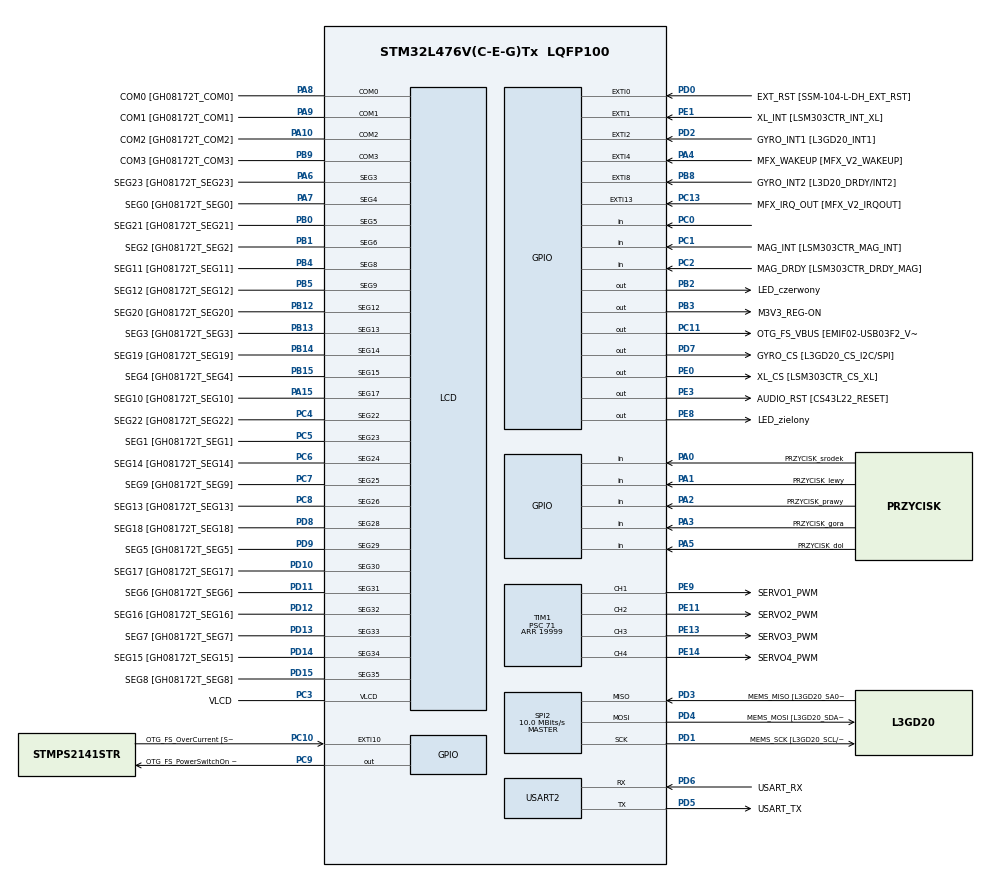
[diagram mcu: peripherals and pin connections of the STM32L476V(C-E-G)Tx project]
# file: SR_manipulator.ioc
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<<<<<<<< HEAD:manipulator/manipulator/manipulator.ioc
========
>>>>>>>> bceb7f419866e076b447dddfbb9c82c1b5c03c72:SR_manipulator/SR_manipulator.ioc
Mcu.Family=STM32L4
Mcu.Name=STM32L476V(C-E-G)Tx
Mcu.Package=LQFP100
<<<<<<<< HEAD:manipulator/manipulator/manipulator.ioc
NVIC.PriorityGroup=NVIC_PRIORITYGROUP_4
PA0.GPIO_Label=JOY_CENTER [MT-008A_CENTER]
========
NVIC.PriorityGroup=NVIC_PRIORITYGROUP_4
PA0.GPIO_Label=PRZYCISK_srodek
>>>>>>>> bceb7f419866e076b447dddfbb9c82c1b5c03c72:SR_manipulator/SR_manipulator.ioc
PA0.GPIO_Mode=GPIO_MODE_INPUT
PA0.GPIO_PuPd=GPIO_PULLDOWN
PA0.Signal=GPIO_Input
<<<<<<<< HEAD:manipulator/manipulator/manipulator.ioc
PA1.GPIO_Label=JOY_LEFT [MT-008A_LEFT]
========
PA1.GPIO_Label=PRZYCISK_lewy
>>>>>>>> bceb7f419866e076b447dddfbb9c82c1b5c03c72:SR_manipulator/SR_manipulator.ioc
PA1.GPIO_Mode=GPIO_MODE_INPUT
PA1.GPIO_PuPd=GPIO_PULLDOWN
PA1.Signal=GPIO_Input
PA10.GPIO_Label=COM2 [GH08172T_COM2]
PA10.GPIO_Mode=GPIO_MODE_AF_PP
PA10.GPIO_PuPd=GPIO_NOPULL
PA10.GPIO_Speed=GPIO_SPEED_FREQ_LOW
PA10.Mode=1/4 Duty Cycle
PA10.Signal=LCD_COM2
PA13\ (JTMS-SWDIO).GPIO_Label=SWDIO
PA13\ (JTMS-SWDIO).Mode=Serial_Wire
PA13\ (JTMS-SWDIO).Signal=SYS_JTMS-SWDIO
PA14\ (JTCK-SWCLK).GPIO_Label=SWCLK
PA14\ (JTCK-SWCLK).Mode=Serial_Wire
PA14\ (JTCK-SWCLK).Signal=SYS_JTCK-SWCLK
PA15\ (JTDI).GPIO_Label=SEG10 [GH08172T_SEG10]
PA15\ (JTDI).GPIO_Mode=GPIO_MODE_AF_PP
PA15\ (JTDI).GPIO_PuPd=GPIO_NOPULL
PA15\ (JTDI).GPIO_Speed=GPIO_SPEED_FREQ_LOW
PA15\ (JTDI).Mode=SEG17
PA15\ (JTDI).Signal=LCD_SEG17
<<<<<<<< HEAD:manipulator/manipulator/manipulator.ioc
PA2.GPIO_Label=JOY_RIGHT [MT-008A_RIGHT]
========
PA2.GPIO_Label=PRZYCISK_prawy
>>>>>>>> bceb7f419866e076b447dddfbb9c82c1b5c03c72:SR_manipulator/SR_manipulator.ioc
PA2.GPIO_Mode=GPIO_MODE_INPUT
PA2.GPIO_PuPd=GPIO_PULLDOWN
PA2.Signal=GPIO_Input
<<<<<<<< HEAD:manipulator/manipulator/manipulator.ioc
PA3.GPIO_Label=JOY_UP [MT-008A_UP]
========
PA3.GPIO_Label=PRZYCISK_gora
>>>>>>>> bceb7f419866e076b447dddfbb9c82c1b5c03c72:SR_manipulator/SR_manipulator.ioc
PA3.GPIO_Mode=GPIO_MODE_INPUT
PA3.GPIO_PuPd=GPIO_PULLDOWN
PA3.Signal=GPIO_Input
PA4.GPIO_Label=MFX_WAKEUP [MFX_V2_WAKEUP]
PA4.GPIO_ModeDefaultEXTI=GPIO_MODE_EVT_RISING
PA4.GPIO_PuPd=GPIO_NOPULL
PA4.Signal=GPXTI4
<<<<<<<< HEAD:manipulator/manipulator/manipulator.ioc
PA5.GPIO_Label=JOY_DOWN [MT-008A_DOWN]
========
PA5.GPIO_Label=PRZYCISK_dol
>>>>>>>> bceb7f419866e076b447dddfbb9c82c1b5c03c72:SR_manipulator/SR_manipulator.ioc
PA5.GPIO_Mode=GPIO_MODE_INPUT
PA5.GPIO_PuPd=GPIO_PULLDOWN
PA5.Signal=GPIO_Input
PA6.GPIO_Label=SEG23 [GH08172T_SEG23]
PA6.GPIO_Mode=GPIO_MODE_AF_PP
PA6.GPIO_PuPd=GPIO_NOPULL
PA6.GPIO_Speed=GPIO_SPEED_FREQ_LOW
PA6.Mode=SEG3
PA6.Signal=LCD_SEG3
PA7.GPIO_Label=SEG0 [GH08172T_SEG0]
PA7.GPIO_Mode=GPIO_MODE_AF_PP
PA7.GPIO_PuPd=GPIO_NOPULL
PA7.GPIO_Speed=GPIO_SPEED_FREQ_LOW
PA7.Mode=SEG4
PA7.Signal=LCD_SEG4
PA8.GPIO_Label=COM0 [GH08172T_COM0]
PA8.GPIO_Mode=GPIO_MODE_AF_PP
PA8.GPIO_PuPd=GPIO_NOPULL
PA8.GPIO_Speed=GPIO_SPEED_FREQ_LOW
PA8.Mode=1/4 Duty Cycle
PA8.Signal=LCD_COM0
PA9.GPIO_Label=COM1 [GH08172T_COM1]
PA9.GPIO_Mode=GPIO_MODE_AF_PP
PA9.GPIO_PuPd=GPIO_NOPULL
PA9.GPIO_Speed=GPIO_SPEED_FREQ_LOW
PA9.Mode=1/4 Duty Cycle
PA9.Signal=LCD_COM1
PB0.GPIO_Label=SEG21 [GH08172T_SEG21]
PB0.GPIO_Mode=GPIO_MODE_AF_PP
PB0.GPIO_PuPd=GPIO_NOPULL
PB0.GPIO_Speed=GPIO_SPEED_FREQ_LOW
PB0.Mode=SEG5
PB0.Signal=LCD_SEG5
PB1.GPIO_Label=SEG2 [GH08172T_SEG2]
PB1.GPIO_Mode=GPIO_MODE_AF_PP
PB1.GPIO_PuPd=GPIO_NOPULL
PB1.GPIO_Speed=GPIO_SPEED_FREQ_LOW
PB1.Mode=SEG6
PB1.Signal=LCD_SEG6
PB12.GPIO_Label=SEG20 [GH08172T_SEG20]
PB12.GPIO_Mode=GPIO_MODE_AF_PP
PB12.GPIO_PuPd=GPIO_NOPULL
PB12.GPIO_Speed=GPIO_SPEED_FREQ_LOW
PB12.Mode=SEG12
PB12.Signal=LCD_SEG12
PB13.GPIO_Label=SEG3 [GH08172T_SEG3]
PB13.GPIO_Mode=GPIO_MODE_AF_PP
PB13.GPIO_PuPd=GPIO_NOPULL
PB13.GPIO_Speed=GPIO_SPEED_FREQ_LOW
PB13.Mode=SEG13
PB13.Signal=LCD_SEG13
PB14.GPIO_Label=SEG19 [GH08172T_SEG19]
PB14.GPIO_Mode=GPIO_MODE_AF_PP
PB14.GPIO_PuPd=GPIO_NOPULL
PB14.GPIO_Speed=GPIO_SPEED_FREQ_LOW
PB14.Mode=SEG14
PB14.Signal=LCD_SEG14
PB15.GPIO_Label=SEG4 [GH08172T_SEG4]
PB15.GPIO_Mode=GPIO_MODE_AF_PP
PB15.GPIO_PuPd=GPIO_NOPULL
PB15.GPIO_Speed=GPIO_SPEED_FREQ_LOW
PB15.Mode=SEG15
PB15.Signal=LCD_SEG15
<<<<<<<< HEAD:manipulator/manipulator/manipulator.ioc
PB2.GPIO_Label=LD_R [LED red]
========
PB2.GPIO_Label=LED_czerwony
>>>>>>>> bceb7f419866e076b447dddfbb9c82c1b5c03c72:SR_manipulator/SR_manipulator.ioc
PB2.GPIO_ModeDefaultOutputPP=GPIO_MODE_OUTPUT_PP
PB2.GPIO_PuPd=GPIO_PULLUP
PB2.GPIO_Speed=GPIO_SPEED_FREQ_VERY_HIGH
PB2.Signal=GPIO_Output
PB3\ (JTDO-TRACESWO).GPIO_Label=M3V3_REG-ON
PB3\ (JTDO-TRACESWO).GPIO_ModeDefaultOutputPP=GPIO_MODE_OUTPUT_PP
PB3\ (JTDO-TRACESWO).GPIO_PuPd=GPIO_NOPULL
PB3\ (JTDO-TRACESWO).GPIO_Speed=GPIO_SPEED_FREQ_LOW
PB3\ (JTDO-TRACESWO).Signal=GPIO_Output
PB4\ (NJTRST).GPIO_Label=SEG11 [GH08172T_SEG11]
PB4\ (NJTRST).GPIO_Mode=GPIO_MODE_AF_PP
PB4\ (NJTRST).GPIO_PuPd=GPIO_NOPULL
PB4\ (NJTRST).GPIO_Speed=GPIO_SPEED_FREQ_LOW
PB4\ (NJTRST).Mode=SEG8
PB4\ (NJTRST).Signal=LCD_SEG8
PB5.GPIO_Label=SEG12 [GH08172T_SEG12]
PB5.GPIO_Mode=GPIO_MODE_AF_PP
PB5.GPIO_PuPd=GPIO_NOPULL
PB5.GPIO_Speed=GPIO_SPEED_FREQ_LOW
PB5.Mode=SEG9
PB5.Signal=LCD_SEG9
PB8.GPIO_Label=GYRO_INT2 [L3D20_DRDY/INT2]
PB8.GPIO_ModeDefaultEXTI=GPIO_MODE_EVT_RISING
PB8.GPIO_PuPd=GPIO_NOPULL
PB8.Signal=GPXTI8
PB9.GPIO_FM9=__NULL
PB9.GPIO_Label=COM3 [GH08172T_COM3]
PB9.GPIO_Mode=GPIO_MODE_AF_PP
PB9.GPIO_PuPd=GPIO_NOPULL
PB9.GPIO_Speed=GPIO_SPEED_FREQ_LOW
PB9.Mode=1/4 Duty Cycle
PB9.Signal=LCD_COM3
PC0.Signal=GPIO_Input
PC1.GPIO_Label=MAG_INT [LSM303CTR_MAG_INT]
PC1.GPIO_Mode=GPIO_MODE_INPUT
PC1.GPIO_PuPd=GPIO_NOPULL
PC1.Signal=GPIO_Input
PC10.GPIO_Label=OTG_FS_OverCurrent [STMPS2141STR_FAULT]
PC10.GPIO_ModeDefaultEXTI=GPIO_MODE_EVT_RISING
PC10.GPIO_PuPd=GPIO_NOPULL
PC10.Signal=GPXTI10
PC11.GPIO_Label=OTG_FS_VBUS [EMIF02-USB03F2_Vbus]
PC11.GPIO_ModeDefaultOutputPP=GPIO_MODE_OUTPUT_PP
PC11.GPIO_PuPd=GPIO_NOPULL
PC11.GPIO_Speed=GPIO_SPEED_FREQ_LOW
PC11.Signal=GPIO_Output
<<<<<<<< HEAD:manipulator/manipulator/manipulator.ioc
PC13.GPIO_Label=MFX_IRQ_OUT [MFX_V2_IRQOUT]
PC13.GPIO_ModeDefaultEXTI=GPIO_MODE_EVT_RISING
PC13.GPIO_PuPd=GPIO_NOPULL
PC13.Signal=GPXTI13
PC14-OSC32_IN\ (PC14).Mode=LSE-External-Oscillator
PC14-OSC32_IN\ (PC14).Signal=RCC_OSC32_IN
PC15-OSC32_OUT\ (PC15).Mode=LSE-External-Oscillator
PC15-OSC32_OUT\ (PC15).Signal=RCC_OSC32_OUT
========
>>>>>>>> bceb7f419866e076b447dddfbb9c82c1b5c03c72:SR_manipulator/SR_manipulator.ioc
PC2.GPIO_Label=MAG_DRDY [LSM303CTR_DRDY_MAG]
PC2.GPIO_Mode=GPIO_MODE_INPUT
PC2.GPIO_PuPd=GPIO_NOPULL
PC2.Signal=GPIO_Input
PC3.GPIO_Label=VLCD
PC3.GPIO_Mode=GPIO_MODE_AF_PP
PC3.GPIO_PuPd=GPIO_NOPULL
PC3.GPIO_Speed=GPIO_SPEED_FREQ_LOW
PC3.Mode=1/4 Duty Cycle
PC3.Signal=LCD_VLCD
PC4.GPIO_Label=SEG22 [GH08172T_SEG22]
PC4.GPIO_Mode=GPIO_MODE_AF_PP
PC4.GPIO_PuPd=GPIO_NOPULL
PC4.GPIO_Speed=GPIO_SPEED_FREQ_LOW
PC4.Mode=SEG22
PC4.Signal=LCD_SEG22
PC5.GPIO_Label=SEG1 [GH08172T_SEG1]
PC5.GPIO_Mode=GPIO_MODE_AF_PP
PC5.GPIO_PuPd=GPIO_NOPULL
PC5.GPIO_Speed=GPIO_SPEED_FREQ_LOW
PC5.Mode=SEG23
PC5.Signal=LCD_SEG23
PC6.GPIO_Label=SEG14 [GH08172T_SEG14]
PC6.GPIO_Mode=GPIO_MODE_AF_PP
PC6.GPIO_PuPd=GPIO_NOPULL
PC6.GPIO_Speed=GPIO_SPEED_FREQ_LOW
PC6.Mode=SEG24
PC6.Signal=LCD_SEG24
PC7.GPIO_Label=SEG9 [GH08172T_SEG9]
PC7.GPIO_Mode=GPIO_MODE_AF_PP
PC7.GPIO_PuPd=GPIO_NOPULL
PC7.GPIO_Speed=GPIO_SPEED_FREQ_LOW
PC7.Mode=SEG25
PC7.Signal=LCD_SEG25
PC8.GPIO_Label=SEG13 [GH08172T_SEG13]
PC8.GPIO_Mode=GPIO_MODE_AF_PP
PC8.GPIO_PuPd=GPIO_NOPULL
PC8.GPIO_Speed=GPIO_SPEED_FREQ_LOW
PC8.Mode=SEG26
PC8.Signal=LCD_SEG26
PC9.GPIO_Label=OTG_FS_PowerSwitchOn [STMPS2141STR_EN]
PC9.GPIO_ModeDefaultOutputPP=GPIO_MODE_OUTPUT_PP
PC9.GPIO_PuPd=GPIO_NOPULL
PC9.GPIO_Speed=GPIO_SPEED_FREQ_LOW
PC9.PinState=GPIO_PIN_SET
PC9.Signal=GPIO_Output
PD0.GPIO_Label=EXT_RST [SSM-104-L-DH_EXT_RST]
PD0.GPIO_ModeDefaultEXTI=GPIO_MODE_EVT_RISING
PD0.GPIO_PuPd=GPIO_NOPULL
PD0.Signal=GPXTI0
PD1.GPIO_Label=MEMS_SCK [L3GD20_SCL/SPC]
PD1.GPIO_Mode=GPIO_MODE_AF_PP
PD1.GPIO_PuPd=GPIO_NOPULL
PD1.GPIO_Speed=GPIO_SPEED_FREQ_VERY_HIGH
PD1.Mode=Full_Duplex_Master
PD1.Signal=SPI2_SCK
PD10.GPIO_Label=SEG17 [GH08172T_SEG17]
PD10.GPIO_Mode=GPIO_MODE_AF_PP
PD10.GPIO_PuPd=GPIO_NOPULL
PD10.GPIO_Speed=GPIO_SPEED_FREQ_LOW
PD10.Mode=SEG30
PD10.Signal=LCD_SEG30
PD11.GPIO_Label=SEG6 [GH08172T_SEG6]
PD11.GPIO_Mode=GPIO_MODE_AF_PP
PD11.GPIO_PuPd=GPIO_NOPULL
PD11.GPIO_Speed=GPIO_SPEED_FREQ_LOW
PD11.Mode=SEG31
PD11.Signal=LCD_SEG31
PD12.GPIO_Label=SEG16 [GH08172T_SEG16]
PD12.GPIO_Mode=GPIO_MODE_AF_PP
PD12.GPIO_PuPd=GPIO_NOPULL
PD12.GPIO_Speed=GPIO_SPEED_FREQ_LOW
PD12.Mode=SEG32
PD12.Signal=LCD_SEG32
PD13.GPIO_Label=SEG7 [GH08172T_SEG7]
PD13.GPIO_Mode=GPIO_MODE_AF_PP
PD13.GPIO_PuPd=GPIO_NOPULL
PD13.GPIO_Speed=GPIO_SPEED_FREQ_LOW
PD13.Mode=SEG33
PD13.Signal=LCD_SEG33
PD14.GPIO_Label=SEG15 [GH08172T_SEG15]
PD14.GPIO_Mode=GPIO_MODE_AF_PP
PD14.GPIO_PuPd=GPIO_NOPULL
PD14.GPIO_Speed=GPIO_SPEED_FREQ_LOW
PD14.Mode=SEG34
PD14.Signal=LCD_SEG34
PD15.GPIO_Label=SEG8 [GH08172T_SEG8]
PD15.GPIO_Mode=GPIO_MODE_AF_PP
PD15.GPIO_PuPd=GPIO_NOPULL
PD15.GPIO_Speed=GPIO_SPEED_FREQ_LOW
PD15.Mode=SEG35
PD15.Signal=LCD_SEG35
PD2.GPIO_Label=GYRO_INT1 [L3GD20_INT1]
PD2.GPIO_ModeDefaultEXTI=GPIO_MODE_EVT_RISING
PD2.GPIO_PuPd=GPIO_NOPULL
PD2.Signal=GPXTI2
PD3.GPIO_Label=MEMS_MISO [L3GD20_SA0/SDO]
PD3.GPIO_Mode=GPIO_MODE_AF_PP
PD3.GPIO_PuPd=GPIO_NOPULL
PD3.GPIO_Speed=GPIO_SPEED_FREQ_VERY_HIGH
PD3.Mode=Full_Duplex_Master
PD3.Signal=SPI2_MISO
PD4.GPIO_Label=MEMS_MOSI [L3GD20_SDA/SDI/SDO]
PD4.GPIO_Mode=GPIO_MODE_AF_PP
PD4.GPIO_PuPd=GPIO_NOPULL
PD4.GPIO_Speed=GPIO_SPEED_FREQ_VERY_HIGH
PD4.Mode=Full_Duplex_Master
PD4.Signal=SPI2_MOSI
PD5.GPIO_Label=USART_TX
PD5.GPIO_Mode=GPIO_MODE_AF_PP
PD5.GPIO_PuPd=GPIO_PULLUP
PD5.GPIO_Speed=GPIO_SPEED_FREQ_VERY_HIGH
PD5.Mode=Asynchronous
PD5.Signal=USART2_TX
PD6.GPIO_Label=USART_RX
PD6.GPIO_Mode=GPIO_MODE_AF_PP
PD6.GPIO_PuPd=GPIO_PULLUP
PD6.GPIO_Speed=GPIO_SPEED_FREQ_VERY_HIGH
PD6.Mode=Asynchronous
PD6.Signal=USART2_RX
PD7.GPIO_Label=GYRO_CS [L3GD20_CS_I2C/SPI]
PD7.GPIO_ModeDefaultOutputPP=GPIO_MODE_OUTPUT_PP
PD7.GPIO_PuPd=GPIO_NOPULL
PD7.GPIO_Speed=GPIO_SPEED_FREQ_VERY_HIGH
PD7.Signal=GPIO_Output
PD8.GPIO_Label=SEG18 [GH08172T_SEG18]
PD8.GPIO_Mode=GPIO_MODE_AF_PP
PD8.GPIO_PuPd=GPIO_NOPULL
PD8.GPIO_Speed=GPIO_SPEED_FREQ_LOW
PD8.Mode=SEG28
PD8.Signal=LCD_SEG28
PD9.GPIO_Label=SEG5 [GH08172T_SEG5]
PD9.GPIO_Mode=GPIO_MODE_AF_PP
PD9.GPIO_PuPd=GPIO_NOPULL
PD9.GPIO_Speed=GPIO_SPEED_FREQ_LOW
PD9.Mode=SEG29
PD9.Signal=LCD_SEG29
PE0.GPIO_Label=XL_CS [LSM303CTR_CS_XL]
PE0.GPIO_ModeDefaultOutputPP=GPIO_MODE_OUTPUT_PP
PE0.GPIO_PuPd=GPIO_NOPULL
PE0.GPIO_Speed=GPIO_SPEED_FREQ_LOW
PE0.Signal=GPIO_Output
PE1.GPIO_Label=XL_INT [LSM303CTR_INT_XL]
PE1.GPIO_ModeDefaultEXTI=GPIO_MODE_EVT_RISING
PE1.GPIO_PuPd=GPIO_NOPULL
PE1.Signal=GPXTI1
<<<<<<<< HEAD:manipulator/manipulator/manipulator.ioc
PE11.Signal=S_TIM1_CH2
PE13.Signal=S_TIM1_CH3
========
PE11.GPIO_Label=SERVO2_PWM
PE11.Signal=S_TIM1_CH2
PE13.GPIO_Label=SERVO3_PWM
PE13.Signal=S_TIM1_CH3
PE14.GPIO_Label=SERVO4_PWM
>>>>>>>> bceb7f419866e076b447dddfbb9c82c1b5c03c72:SR_manipulator/SR_manipulator.ioc
PE14.Signal=S_TIM1_CH4
PE3.GPIO_Label=AUDIO_RST [CS43L22_RESET]
PE3.GPIO_ModeDefaultOutputPP=GPIO_MODE_OUTPUT_PP
PE3.GPIO_PuPd=GPIO_NOPULL
PE3.GPIO_Speed=GPIO_SPEED_FREQ_HIGH
PE3.Signal=GPIO_Output
<<<<<<<< HEAD:manipulator/manipulator/manipulator.ioc
PE8.GPIO_Label=LD_G [LED_Green]
========
PE8.GPIO_Label=LED_zielony
>>>>>>>> bceb7f419866e076b447dddfbb9c82c1b5c03c72:SR_manipulator/SR_manipulator.ioc
PE8.GPIO_ModeDefaultOutputPP=GPIO_MODE_OUTPUT_PP
PE8.GPIO_PuPd=GPIO_PULLUP
PE8.GPIO_Speed=GPIO_SPEED_FREQ_VERY_HIGH
PE8.Signal=GPIO_Output
<<<<<<<< HEAD:manipulator/manipulator/manipulator.ioc
PE9.Signal=S_TIM1_CH1
PH0-OSC_IN\ (PH0).Mode=HSE-External-Oscillator
PH0-OSC_IN\ (PH0).Signal=RCC_OSC_IN
PH1-OSC_OUT\ (PH1).Mode=HSE-External-Oscillator
PH1-OSC_OUT\ (PH1).Signal=RCC_OSC_OUT
========
PE9.GPIO_Label=SERVO1_PWM
PE9.Signal=S_TIM1_CH1
>>>>>>>> bceb7f419866e076b447dddfbb9c82c1b5c03c72:SR_manipulator/SR_manipulator.ioc
<<<<<<<< HEAD:manipulator/manipulator/manipulator.ioc
========
>>>>>>>> bceb7f419866e076b447dddfbb9c82c1b5c03c72:SR_manipulator/SR_manipulator.ioc
ProjectManager.HeapSize=0x200
<<<<<<<< HEAD:manipulator/manipulator/manipulator.ioc
========
>>>>>>>> bceb7f419866e076b447dddfbb9c82c1b5c03c72:SR_manipulator/SR_manipulator.ioc
ProjectManager.StackSize=0x400
ProjectManager.TargetToolchain=STM32CubeIDE
<<<<<<<< HEAD:manipulator/manipulator/manipulator.ioc
RCC.ADCFreq_Value=48000000
RCC.AHBFreq_Value=72000000
RCC.APB1Freq_Value=72000000
RCC.APB1TimFreq_Value=72000000
RCC.APB2Freq_Value=72000000
RCC.APB2TimFreq_Value=72000000
RCC.CortexFreq_Value=72000000
RCC.HCLKFreq_Value=72000000
RCC.HSE_VALUE=8000000
RCC.HSI_VALUE=16000000
RCC.MSI_VALUE=4000000
RCC.PLLN=36
========
RCC.ADCFreq_Value=48000000
RCC.AHBCLKDivider=RCC_SYSCLK_DIV2
RCC.AHBFreq_Value=20000000
RCC.APB1Freq_Value=20000000
RCC.APB1TimFreq_Value=20000000
RCC.APB2Freq_Value=20000000
RCC.APB2TimFreq_Value=20000000
RCC.CortexFreq_Value=20000000
RCC.HCLKFreq_Value=20000000
RCC.HSE_VALUE=8000000
RCC.HSI_VALUE=16000000
RCC.LSE_VALUE=32768
RCC.MSI_VALUE=4000000
RCC.PLLN=20
>>>>>>>> bceb7f419866e076b447dddfbb9c82c1b5c03c72:SR_manipulator/SR_manipulator.ioc
RCC.PLLSAI1N=24
RCC.PREFETCH_ENABLE=1
<<<<<<<< HEAD:manipulator/manipulator/manipulator.ioc
========
>>>>>>>> bceb7f419866e076b447dddfbb9c82c1b5c03c72:SR_manipulator/SR_manipulator.ioc
<<<<<<<< HEAD:manipulator/manipulator/manipulator.ioc
RCC.SYSCLKFreq_VALUE=72000000
RCC.SYSCLKSource=RCC_SYSCLKSOURCE_PLLCLK
RCC.USBFreq_Value=48000000
RCC.VCOOutputFreq_Value=144000000
========
RCC.SYSCLKFreq_VALUE=40000000
RCC.SYSCLKSource=RCC_SYSCLKSOURCE_PLLCLK
RCC.USBFreq_Value=48000000
RCC.VCOOutputFreq_Value=80000000
>>>>>>>> bceb7f419866e076b447dddfbb9c82c1b5c03c72:SR_manipulator/SR_manipulator.ioc
<<<<<<<< HEAD:manipulator/manipulator/manipulator.ioc
========
>>>>>>>> bceb7f419866e076b447dddfbb9c82c1b5c03c72:SR_manipulator/SR_manipulator.ioc
SH.S_TIM1_CH1.0=TIM1_CH1,PWM Generation1 CH1
SH.S_TIM1_CH2.0=TIM1_CH2,PWM Generation2 CH2
SH.S_TIM1_CH3.0=TIM1_CH3,PWM Generation3 CH3
SH.S_TIM1_CH4.0=TIM1_CH4,PWM Generation4 CH4
<<<<<<<< HEAD:manipulator/manipulator/manipulator.ioc
SPI2.CalculateBaudRate=36.0 MBits/s
SPI2.Direction=SPI_DIRECTION_2LINES
SPI2.Mode=SPI_MODE_MASTER
SPI2.VirtualType=VM_MASTER
TIM1.AutoReloadPreload=TIM_AUTORELOAD_PRELOAD_ENABLE
========
SPI2.CalculateBaudRate=10.0 MBits/s
SPI2.Direction=SPI_DIRECTION_2LINES
SPI2.Mode=SPI_MODE_MASTER
SPI2.VirtualType=VM_MASTER
>>>>>>>> bceb7f419866e076b447dddfbb9c82c1b5c03c72:SR_manipulator/SR_manipulator.ioc
TIM1.Channel-PWM\ Generation1\ CH1=TIM_CHANNEL_1
TIM1.Channel-PWM\ Generation2\ CH2=TIM_CHANNEL_2
TIM1.Channel-PWM\ Generation3\ CH3=TIM_CHANNEL_3
TIM1.Channel-PWM\ Generation4\ CH4=TIM_CHANNEL_4
<<<<<<<< HEAD:manipulator/manipulator/manipulator.ioc
TIM1.Period=19999
TIM1.Prescaler=71
========
>>>>>>>> bceb7f419866e076b447dddfbb9c82c1b5c03c72:SR_manipulator/SR_manipulator.ioc
USART2.VirtualMode-Asynchronous=VM_ASYNC
board=STM32L476G-DISCO

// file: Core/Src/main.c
/* USER CODE BEGIN Header */
/**
  ******************************************************************************
  * @file           : main.c
  * @brief          : Main program body
  ******************************************************************************
  * @attention
  *
<<<<<<<< HEAD:manipulator/manipulator/Core/Src/main.c
  * <h2><center>&copy; Copyright (c) 2024 STMicroelectronics.
  * All rights reserved.</center></h2>
  *
  * This software component is licensed by ST under Ultimate Liberty license
  * SLA0044, the "License"; You may not use this file except in compliance with
  * the License. You may obtain a copy of the License at:
  *                             www.st.com/SLA0044
========
  * Copyright (c) 2024 STMicroelectronics.
  * All rights reserved.
  *
  * This software is licensed under terms that can be found in the LICENSE file
  * in the root directory of this software component.
  * If no LICENSE file comes with this software, it is provided AS-IS.
>>>>>>>> bceb7f419866e076b447dddfbb9c82c1b5c03c72:SR_manipulator/Core/Src/main.c
  *
  ******************************************************************************
  */
/* USER CODE END Header */
#include "main.h"
#include "lcd.h"
#include "spi.h"
#include "tim.h"
#include "usart.h"
#include "gpio.h"

/* USER CODE BEGIN Includes */
<<<<<<<< HEAD:manipulator/manipulator/Core/Src/main.c
#include "stm32l476g_discovery_glass_lcd.h"
#include "stm32l476g_discovery_compass.h"
#include "stdint.h"
#include "stdio.h"
#include "string.h"
========
#include "../../Drivers/BSP/devices/stm32l476g_discovery_glass_lcd.h"
#include "../../Drivers/BSP/devices/stm32l476g_discovery_gyroscope.h"

>>>>>>>> bceb7f419866e076b447dddfbb9c82c1b5c03c72:SR_manipulator/Core/Src/main.c
/* USER CODE END Includes */

/* USER CODE BEGIN PM */
<<<<<<<< HEAD:manipulator/manipulator/Core/Src/main.c
#define MIDDLE HAL_GPIO_ReadPin(GPIOA, GPIO_PIN_0)
#define LEFT HAL_GPIO_ReadPin(GPIOA, GPIO_PIN_1)
#define RIGHT HAL_GPIO_ReadPin(GPIOA, GPIO_PIN_2)
#define UP HAL_GPIO_ReadPin(GPIOA, GPIO_PIN_3)
#define DOWN HAL_GPIO_ReadPin(GPIOA, GPIO_PIN_5)
========
#define SRODEK HAL_GPIO_ReadPin(GPIOA, GPIO_PIN_0)
#define LEWO HAL_GPIO_ReadPin(GPIOA, GPIO_PIN_1)
#define PRAWO HAL_GPIO_ReadPin(GPIOA, GPIO_PIN_2)
#define GORA HAL_GPIO_ReadPin(GPIOA, GPIO_PIN_3)
#define DOL HAL_GPIO_ReadPin(GPIOA, GPIO_PIN_5)
>>>>>>>> bceb7f419866e076b447dddfbb9c82c1b5c03c72:SR_manipulator/Core/Src/main.c
/* USER CODE END PM */

/* USER CODE BEGIN PV */
<<<<<<<< HEAD:manipulator/manipulator/Core/Src/main.c
int16_t pDataXYZ[3];
uint8_t click;
int last;
int odczyt[4], current[4];
char buf[16];
========
float Data[3];
uint8_t klick, klick_modulo;
>>>>>>>> bceb7f419866e076b447dddfbb9c82c1b5c03c72:SR_manipulator/Core/Src/main.c
/* USER CODE END PV */

void SystemClock_Config(void);

/* USER CODE BEGIN 0 */

<<<<<<<< HEAD:manipulator/manipulator/Core/Src/main.c
int _write(int file, char *ptr, int len){
	HAL_UART_Transmit(&huart2, (uint8_t*)ptr, len, 50);
	return len;
}

========
>>>>>>>> bceb7f419866e076b447dddfbb9c82c1b5c03c72:SR_manipulator/Core/Src/main.c
/* USER CODE END 0 */

int main(void)
{

  /* MCU Configuration--------------------------------------------------------*/

  /* Reset of all peripherals, Initializes the Flash interface and the Systick. */
  HAL_Init();

  /* Configure the system clock */
  SystemClock_Config();

  /* Initialize all configured peripherals */
  MX_GPIO_Init();
  MX_LCD_Init();
  MX_SPI2_Init();
  MX_USART2_UART_Init();
  MX_TIM1_Init();
  /* USER CODE BEGIN 2 */
<<<<<<<< HEAD:manipulator/manipulator/Core/Src/main.c
  BSP_LCD_GLASS_Init();
  BSP_COMPASS_Init();
  //HAL_TIM_PWM_Start(&htim1, TIM_CHANNEL_1);
  //HAL_TIM_PWM_Start(&htim1, TIM_CHANNEL_2);
  //HAL_TIM_PWM_Start(&htim1, TIM_CHANNEL_3);
  HAL_TIM_PWM_Start(&htim1, TIM_CHANNEL_4);

========
  BSP_GYRO_Init();
  BSP_LCD_GLASS_Init();
>>>>>>>> bceb7f419866e076b447dddfbb9c82c1b5c03c72:SR_manipulator/Core/Src/main.c
  /* USER CODE END 2 */

  /* Infinite loop */
  while (1)
  {

    /* USER CODE BEGIN 3 */
<<<<<<<< HEAD:manipulator/manipulator/Core/Src/main.c

	   /*
	    * accelerometer
	    */

	  	BSP_COMPASS_AccGetXYZ(pDataXYZ);

	   /*
	    * LCD display
	    */

	  	last = HAL_GetTick();

	  	if(UP == GPIO_PIN_SET){odczyt[0] = 1;}
	  		if(!(UP == GPIO_PIN_SET) && odczyt[0] == 1){
	  			odczyt[0] = 0;
	  			current[0] = HAL_GetTick();
	  			if((current[0] - last) < 50){
	  				click++;
	  				last = current[0];
	  			}
	  		}

	  	last = HAL_GetTick();

		if(DOWN == GPIO_PIN_SET){odczyt[1] = 1;}
			if(!(DOWN == GPIO_PIN_SET) && odczyt[1] == 1){
				odczyt[1] = 0;
				current[1] = HAL_GetTick();
				if((current[1] - last) < 50){
					click--;
					last = current[1];
				}
			}

		BSP_LCD_GLASS_Clear();
		switch(click%3){
		  case 0:
			sprintf(buf, "X%d", pDataXYZ[0]);
			BSP_LCD_GLASS_DisplayString((uint8_t*)&buf);
			break;
		  case 1:
		    sprintf(buf, "Y%d", pDataXYZ[1]);
			BSP_LCD_GLASS_DisplayString((uint8_t*)&buf);
			break;
		  case 2:
			sprintf(buf, "Z%d", pDataXYZ[2]);
			BSP_LCD_GLASS_DisplayString((uint8_t*)&buf);
			break;
		}

		HAL_Delay(250);

	    /*
	     * Actuators - joints
	     */

	    // first one
	    //__HAL_TIM_SET_COMPARE(&htim1, TIM_CHANNEL_1, 1000);

	    // second one
	    /*__HAL_TIM_SET_COMPARE(&htim1, TIM_CHANNEL_2, 1000);
	    HAL_Delay(2000);
	    __HAL_TIM_SET_COMPARE(&htim1, TIM_CHANNEL_2, 1500);
	 	HAL_Delay(2000);*/

	    // third one
	    /*__HAL_TIM_SET_COMPARE(&htim1, TIM_CHANNEL_3, 1000);
	    HAL_Delay(2000);
	    __HAL_TIM_SET_COMPARE(&htim1, TIM_CHANNEL_3, 1700);
	    HAL_Delay(2000);*/

	    /*
	     * End effector
	     */

		last = HAL_GetTick();

		if(RIGHT == GPIO_PIN_SET){odczyt[2] = 1;}
				if(!(RIGHT == GPIO_PIN_SET) && odczyt[2] == 1){
					odczyt[2] = 0;
					current[2] = HAL_GetTick();
					if((current[2] - last) < 50){
						__HAL_TIM_SET_COMPARE(&htim1, TIM_CHANNEL_4, 500);
						HAL_Delay(250);
						last = current[2];
					}
				}

		last = HAL_GetTick();

		if(LEFT == GPIO_PIN_SET){odczyt[3] = 1;}
				if(!(LEFT == GPIO_PIN_SET) && odczyt[3] == 1){
					odczyt[3] = 0;
					current[3] = HAL_GetTick();
					if((current[3] - last) < 50){
						__HAL_TIM_SET_COMPARE(&htim1, TIM_CHANNEL_4, 2500);
						HAL_Delay(250);
						last = current[3];
					}
				}

========
    BSP_LCD_GLASS_Clear();

    // accelerometer
    BSP_GYRO_GetXYZ(Data);
    // LCD
    // przycisk
    if(GORA) {
    	klick++;
    }

    if(DOL) {
    	klick--;
    }

    klick_modulo=klick%3;

    switch(klick_modulo){
    case 0:
    	BSP_LCD_GLASS_DisplayChar((uint8_t*)"X", POINT_OFF, DOUBLEPOINT_ON, 0);
    	break;
    case 1:
    	BSP_LCD_GLASS_DisplayChar((uint8_t*)"Y", POINT_OFF, DOUBLEPOINT_ON, 0);
        break;
    case 2:
    	BSP_LCD_GLASS_DisplayChar((uint8_t*)"Z", POINT_OFF, DOUBLEPOINT_ON, 0);
        break;
    }

    //
    HAL_Delay(500);
>>>>>>>> bceb7f419866e076b447dddfbb9c82c1b5c03c72:SR_manipulator/Core/Src/main.c
  }
  /* USER CODE END 3 */
}

void SystemClock_Config(void)
{
  RCC_OscInitTypeDef RCC_OscInitStruct = {0};
  RCC_ClkInitTypeDef RCC_ClkInitStruct = {0};
<<<<<<<< HEAD:manipulator/manipulator/Core/Src/main.c
  RCC_PeriphCLKInitTypeDef PeriphClkInit = {0};

  /** Configure LSE Drive Capability
  */
  HAL_PWR_EnableBkUpAccess();
  __HAL_RCC_LSEDRIVE_CONFIG(RCC_LSEDRIVE_LOW);
  /** Initializes the RCC Oscillators according to the specified parameters
  * in the RCC_OscInitTypeDef structure.
  */
  RCC_OscInitStruct.OscillatorType = RCC_OSCILLATORTYPE_LSI|RCC_OSCILLATORTYPE_LSE
                              |RCC_OSCILLATORTYPE_MSI;
  RCC_OscInitStruct.LSEState = RCC_LSE_ON;
========

  /** Configure the main internal regulator output voltage
  */
  if (HAL_PWREx_ControlVoltageScaling(PWR_REGULATOR_VOLTAGE_SCALE1) != HAL_OK)
  {
    Error_Handler();
  }

  /** Initializes the RCC Oscillators according to the specified parameters
  * in the RCC_OscInitTypeDef structure.
  */
  RCC_OscInitStruct.OscillatorType = RCC_OSCILLATORTYPE_LSI|RCC_OSCILLATORTYPE_MSI;
>>>>>>>> bceb7f419866e076b447dddfbb9c82c1b5c03c72:SR_manipulator/Core/Src/main.c
  RCC_OscInitStruct.LSIState = RCC_LSI_ON;
  RCC_OscInitStruct.MSIState = RCC_MSI_ON;
  RCC_OscInitStruct.MSICalibrationValue = 0;
  RCC_OscInitStruct.MSIClockRange = RCC_MSIRANGE_6;
  RCC_OscInitStruct.PLL.PLLState = RCC_PLL_ON;
  RCC_OscInitStruct.PLL.PLLSource = RCC_PLLSOURCE_MSI;
  RCC_OscInitStruct.PLL.PLLM = 1;
<<<<<<<< HEAD:manipulator/manipulator/Core/Src/main.c
  RCC_OscInitStruct.PLL.PLLN = 36;
========
  RCC_OscInitStruct.PLL.PLLN = 20;
>>>>>>>> bceb7f419866e076b447dddfbb9c82c1b5c03c72:SR_manipulator/Core/Src/main.c
  RCC_OscInitStruct.PLL.PLLP = RCC_PLLP_DIV7;
  RCC_OscInitStruct.PLL.PLLQ = RCC_PLLQ_DIV2;
  RCC_OscInitStruct.PLL.PLLR = RCC_PLLR_DIV2;
  if (HAL_RCC_OscConfig(&RCC_OscInitStruct) != HAL_OK)
  {
    Error_Handler();
  }
<<<<<<<< HEAD:manipulator/manipulator/Core/Src/main.c
========

>>>>>>>> bceb7f419866e076b447dddfbb9c82c1b5c03c72:SR_manipulator/Core/Src/main.c
  /** Initializes the CPU, AHB and APB buses clocks
  */
  RCC_ClkInitStruct.ClockType = RCC_CLOCKTYPE_HCLK|RCC_CLOCKTYPE_SYSCLK
                              |RCC_CLOCKTYPE_PCLK1|RCC_CLOCKTYPE_PCLK2;
  RCC_ClkInitStruct.SYSCLKSource = RCC_SYSCLKSOURCE_PLLCLK;
<<<<<<<< HEAD:manipulator/manipulator/Core/Src/main.c
  RCC_ClkInitStruct.AHBCLKDivider = RCC_SYSCLK_DIV1;
  RCC_ClkInitStruct.APB1CLKDivider = RCC_HCLK_DIV1;
  RCC_ClkInitStruct.APB2CLKDivider = RCC_HCLK_DIV1;

  if (HAL_RCC_ClockConfig(&RCC_ClkInitStruct, FLASH_LATENCY_4) != HAL_OK)
  {
    Error_Handler();
  }
  PeriphClkInit.PeriphClockSelection = RCC_PERIPHCLK_RTC|RCC_PERIPHCLK_USART2;
  PeriphClkInit.Usart2ClockSelection = RCC_USART2CLKSOURCE_PCLK1;
  PeriphClkInit.RTCClockSelection = RCC_RTCCLKSOURCE_LSI;
  if (HAL_RCCEx_PeriphCLKConfig(&PeriphClkInit) != HAL_OK)
  {
    Error_Handler();
  }
  /** Configure the main internal regulator output voltage
  */
  if (HAL_PWREx_ControlVoltageScaling(PWR_REGULATOR_VOLTAGE_SCALE1) != HAL_OK)
  {
    Error_Handler();
  }
  /** Enable MSI Auto calibration
  */
  HAL_RCCEx_EnableMSIPLLMode();
========
  RCC_ClkInitStruct.AHBCLKDivider = RCC_SYSCLK_DIV2;
  RCC_ClkInitStruct.APB1CLKDivider = RCC_HCLK_DIV1;
  RCC_ClkInitStruct.APB2CLKDivider = RCC_HCLK_DIV1;

  if (HAL_RCC_ClockConfig(&RCC_ClkInitStruct, FLASH_LATENCY_1) != HAL_OK)
  {
    Error_Handler();
  }
>>>>>>>> bceb7f419866e076b447dddfbb9c82c1b5c03c72:SR_manipulator/Core/Src/main.c
}

void Error_Handler(void)
{
  /* USER CODE BEGIN Error_Handler_Debug */
  /* User can add his own implementation to report the HAL error return state */
<<<<<<<< HEAD:manipulator/manipulator/Core/Src/main.c

========
  __disable_irq();
  while (1)
  {
  }
>>>>>>>> bceb7f419866e076b447dddfbb9c82c1b5c03c72:SR_manipulator/Core/Src/main.c
  /* USER CODE END Error_Handler_Debug */
}

#ifdef  USE_FULL_ASSERT
/**
  * @brief  Reports the name of the source file and the source line number
  *         where the assert_param error has occurred.
  * @param  file: pointer to the source file name
  * @param  line: assert_param error line source number
  * @retval None
  */
void assert_failed(uint8_t *file, uint32_t line)
{
  /* USER CODE BEGIN 6 */
  /* User can add his own implementation to report the file name and line number,
<<<<<<<< HEAD:manipulator/manipulator/Core/Src/main.c
     tex: printf("Wrong parameters value: file %s on line %d\r\n", file, line) */
  /* USER CODE END 6 */
}
#endif /* USE_FULL_ASSERT */

/************************ (C) COPYRIGHT STMicroelectronics *****END OF FILE****/
========
     ex: printf("Wrong parameters value: file %s on line %d\r\n", file, line) */
  /* USER CODE END 6 */
}
#endif /* USE_FULL_ASSERT */
>>>>>>>> bceb7f419866e076b447dddfbb9c82c1b5c03c72:SR_manipulator/Core/Src/main.c
